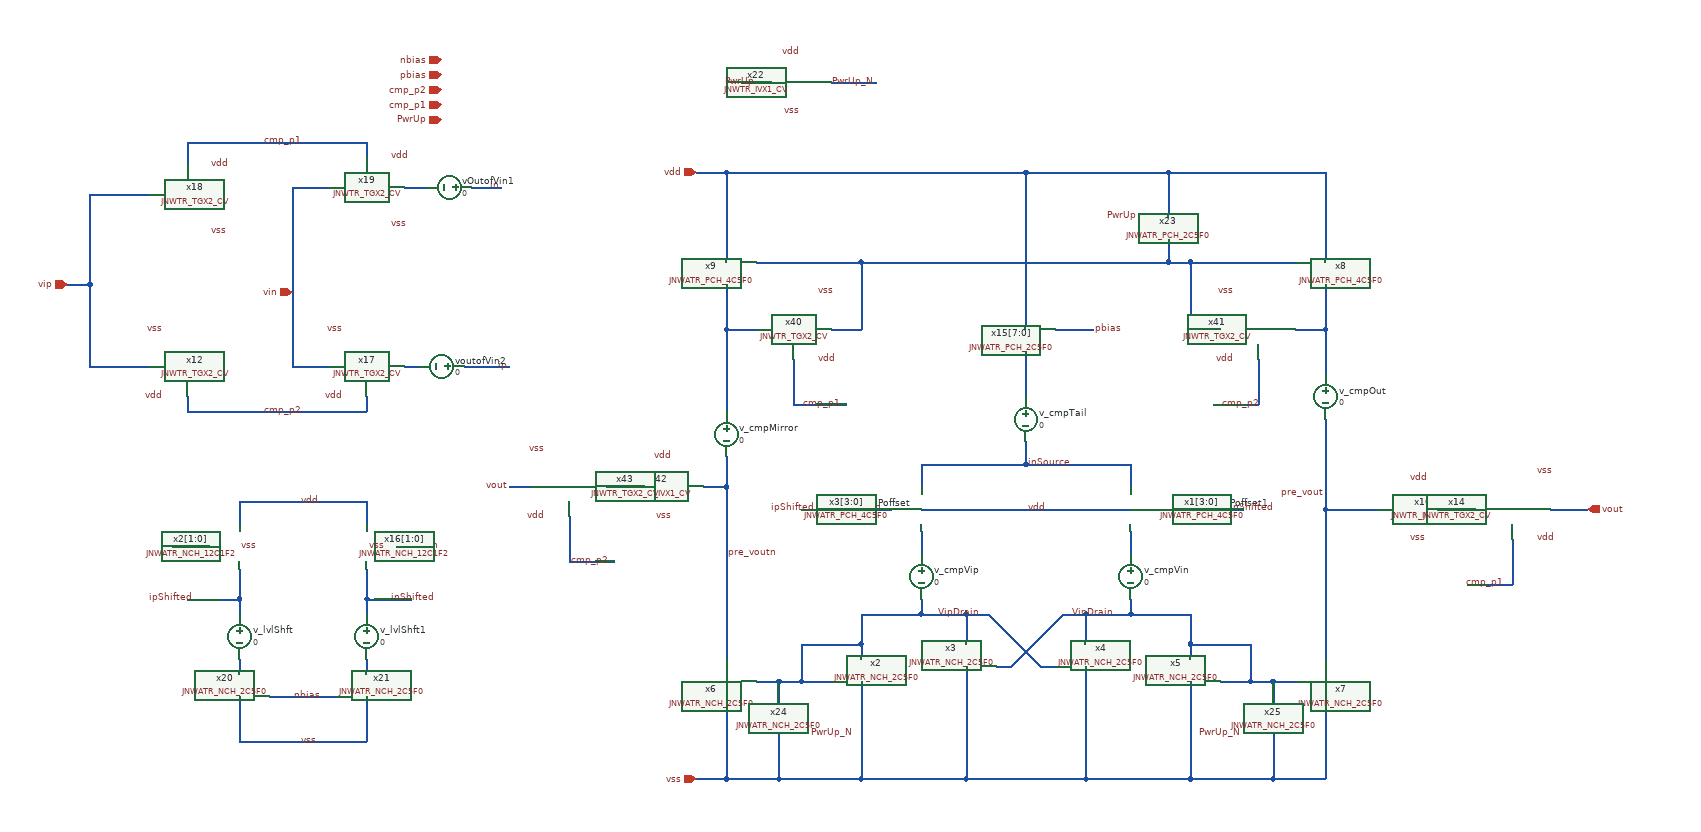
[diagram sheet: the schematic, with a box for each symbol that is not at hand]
v {xschem version=3.4.6 file_version=1.2}
G {}
K {}
V {}
S {}
E {}
N 1470 -450 1470 -410 {
lab=VipDrain}
N 1550 -450 1610 -450 {
lab=VipDrain}
N 1610 -450 1610 -410 {
lab=VipDrain}
N 1770 -450 1770 -410 {
lab=VinDrain}
N 1830 -450 1910 -450 {
lab=VinDrain}
N 1910 -410 1910 -390 {
lab=VinDrain}
N 1650 -380 1670 -380 {
lab=VinDrain}
N 1670 -380 1740 -450 {
lab=VinDrain}
N 1710 -380 1730 -380 {
lab=VipDrain}
N 1640 -450 1710 -380 {
lab=VipDrain}
N 1610 -450 1640 -450 {
lab=VipDrain}
N 1740 -450 1770 -450 {
lab=VinDrain}
N 1610 -380 1610 -230 {
lab=vss}
N 1770 -380 1770 -230 {
lab=vss}
N 2020 -230 2090 -230 {
lab=vss}
N 1470 -230 1610 -230 {
lab=vss}
N 1610 -230 1770 -230 {
lab=vss}
N 1770 -230 1910 -230 {
lab=vss}
N 1910 -360 1910 -230 {
lab=vss}
N 1470 -360 1470 -230 {
lab=vss}
N 1390 -360 1430 -360 {
lab=VipDrain}
N 1390 -410 1470 -410 {
lab=VipDrain}
N 1390 -410 1390 -360 {
lab=VipDrain}
N 1360 -360 1390 -360 {
lab=VipDrain}
N 1470 -410 1470 -390 {
lab=VipDrain}
N 1990 -410 1990 -360 {
lab=VinDrain}
N 1910 -410 1990 -410 {
lab=VinDrain}
N 1910 -450 1910 -410 {
lab=VinDrain}
N 1950 -360 1990 -360 {
lab=VinDrain}
N 1290 -360 1290 -230 {
lab=vss}
N 2090 -360 2090 -230 {
lab=vss}
N 2090 -590 2090 -390 {
lab=pre_vout}
N 2020 -360 2050 -360 {
lab=VinDrain}
N 1470 -920 1470 -830 {
lab=#net1}
N 1330 -920 1470 -920 {
lab=#net1}
N 1290 -1040 1290 -920 {
lab=vdd}
N 2090 -1040 2090 -920 {
lab=vdd}
N 1250 -1040 1290 -1040 {
lab=vdd}
N 1360 -230 1470 -230 {
lab=vss}
N 1250 -230 1290 -230 {
lab=vss}
N 2090 -590 2160 -590 {
lab=pre_vout}
N 1550 -650 1550 -620 {
lab=inSource}
N 1830 -650 1830 -620 {
lab=inSource}
N 1290 -830 1290 -720 {
lab=#net2}
N 2340 -550 2340 -490 {
lab=cmp_p1}
N 2280 -490 2340 -490 {
lab=cmp_p1}
N 2390 -590 2440 -590 {
lab=vout}
N 440 -890 440 -780 {
lab=vip}
N 440 -1010 520 -1010 {
lab=vip}
N 440 -780 520 -780 {
lab=vip}
N 710 -1020 710 -780 {
lab=vin}
N 710 -1020 760 -1020 {
lab=vin}
N 710 -780 760 -780 {
lab=vin}
N 570 -740 570 -720 {
lab=cmp_p2}
N 570 -720 810 -720 {
lab=cmp_p2}
N 810 -740 810 -720 {
lab=cmp_p2}
N 570 -1080 570 -1050 {
lab=cmp_p1}
N 570 -1080 810 -1080 {
lab=cmp_p1}
N 810 -1080 810 -1060 {
lab=cmp_p1}
N 1690 -1040 1690 -830 {lab=vdd}
N 1290 -1040 1690 -1040 {
lab=vdd}
N 1690 -680 1690 -650 {lab=inSource}
N 1390 -590 1420 -590 {lab=ipShifted}
N 1480 -590 1510 -590 {lab=ipm}
N 440 -1010 440 -890 {
lab=vip}
N 1870 -590 1890 -590 {lab=#net3}
N 1950 -590 1980 -590 {lab=inShifted}
N 1290 -620 1290 -390 {lab=pre_voutn}
N 2090 -710 2090 -590 {lab=pre_vout}
N 1830 -560 1830 -530 {lab=#net4}
N 1830 -470 1830 -450 {lab=VinDrain}
N 1770 -450 1830 -450 {
lab=VinDrain}
N 1550 -560 1550 -530 {lab=#net5}
N 1550 -470 1550 -450 {lab=VipDrain}
N 1470 -450 1550 -450 {
lab=VipDrain}
N 1730 -830 1780 -830 {lab=pbias}
N 1690 -800 1690 -740 {lab=#net6}
N 550 -540 600 -540 {lab=ip}
N 1550 -650 1690 -650 {
lab=inSource}
N 1690 -650 1830 -650 {
lab=inSource}
N 1550 -590 1830 -590 {lab=vdd}
N 640 -600 810 -600 {lab=vdd}
N 640 -600 640 -570 {lab=vdd}
N 810 -600 810 -570 {lab=vdd}
N 680 -340 770 -340 {lab=nbias}
N 850 -540 890 -540 {lab=in}
N 810 -340 810 -280 {lab=vss}
N 640 -280 810 -280 {lab=vss}
N 640 -340 640 -280 {lab=vss}
N 570 -470 640 -470 {lab=ipShifted}
N 810 -470 870 -470 {lab=inShifted}
N 810 -510 810 -470 {lab=inShifted}
N 640 -510 640 -470 {lab=ipShifted}
N 810 -470 810 -450 {lab=inShifted}
N 810 -390 810 -370 {lab=#net7}
N 640 -470 640 -450 {lab=ipShifted}
N 640 -390 640 -370 {lab=#net8}
N 410 -890 440 -890 {lab=vip}
N 1310 -1160 1350 -1160 {lab=PwrUp}
N 1430 -1160 1490 -1160 {lab=PwrUp_N}
N 1880 -950 1880 -920 {lab=#net1}
N 1910 -920 2050 -920 {lab=#net1}
N 1470 -920 1880 -920 {
lab=#net1}
N 1880 -1040 1880 -980 {lab=vdd}
N 1880 -1040 2090 -1040 {lab=vdd}
N 1690 -1040 1880 -1040 {
lab=vdd}
N 1360 -360 1360 -320 {lab=VipDrain}
N 1330 -360 1360 -360 {
lab=VipDrain}
N 1290 -230 1360 -230 {
lab=vss}
N 1360 -290 1360 -230 {lab=vss}
N 2020 -360 2020 -320 {lab=VinDrain}
N 2020 -290 2020 -230 {lab=vss}
N 1990 -360 2020 -360 {
lab=VinDrain}
N 1910 -230 2020 -230 {
lab=vss}
N 860 -780 880 -780 {lab=#net9}
N 940 -780 1000 -780 {lab=ip}
N 860 -1020 890 -1020 {lab=#net10}
N 950 -1020 990 -1020 {lab=in}
N 2240 -590 2290 -590 {lab=#net11}
N 1880 -920 1910 -920 {lab=#net1}
N 1910 -920 1910 -830 {lab=#net1}
N 1430 -830 1470 -830 {
lab=#net1}
N 1380 -790 1380 -730 {
lab=cmp_p1}
N 1380 -730 1450 -730 {
lab=cmp_p1}
N 2000 -790 2000 -730 {
lab=cmp_p2}
N 1940 -730 2000 -730 {
lab=cmp_p2}
N 1290 -830 1330 -830 {lab=#net2}
N 1290 -890 1290 -830 {
lab=#net2}
N 2050 -830 2090 -830 {lab=#net12}
N 2090 -830 2090 -770 {lab=#net12}
N 2090 -890 2090 -830 {lab=#net12}
N 1910 -830 1950 -830 {lab=#net1}
N 1130 -620 1180 -620 {
lab=#net13}
N 1080 -580 1080 -520 {
lab=cmp_p2}
N 1080 -520 1140 -520 {
lab=cmp_p2}
N 1000 -620 1030 -620 {
lab=vout}
N 1260 -620 1290 -620 {lab=pre_voutn}
N 1290 -660 1290 -620 {lab=pre_voutn}
C {devices/ipin.sym} 1250 -230 0 0 {name=p2 lab=vss
}
C {devices/ipin.sym} 1250 -1040 0 0 {name=p3 lab=vdd
}
C {devices/ipin.sym} 910 -1170 0 0 {name=p1 lab=pbias
}
C {devices/ipin.sym} 710 -880 0 0 {name=p5 lab=vin
}
C {devices/ipin.sym} 410 -890 0 0 {name=p6 lab=vip
}
C {JNW_ATR_SKY130A/JNWATR_NCH_2C5F0.sym} 1430 -360 0 0 {name=x2 }
C {JNW_ATR_SKY130A/JNWATR_NCH_2C5F0.sym} 1650 -380 0 1 {name=x3 }
C {JNW_ATR_SKY130A/JNWATR_NCH_2C5F0.sym} 1730 -380 0 0 {name=x4 }
C {JNW_ATR_SKY130A/JNWATR_NCH_2C5F0.sym} 1950 -360 0 1 {name=x5 }
C {JNW_ATR_SKY130A/JNWATR_NCH_2C5F0.sym} 1330 -360 0 1 {name=x6 }
C {JNW_ATR_SKY130A/JNWATR_NCH_2C5F0.sym} 2050 -360 0 0 {name=x7 }
C {JNW_ATR_SKY130A/JNWATR_PCH_4C5F0.sym} 2050 -920 0 0 {name=x8 }
C {JNW_ATR_SKY130A/JNWATR_PCH_4C5F0.sym} 1330 -920 0 1 {name=x9 }
C {devices/opin.sym} 2440 -590 0 0 {name=p7 lab=vout}
C {JNW_TR_SKY130A/JNWTR_IVX1_CV.sym} 2160 -590 0 0 {name=x10 }
C {devices/ipin.sym} 910 -1130 0 0 {name=p10 lab=cmp_p1
}
C {devices/lab_wire.sym} 2200 -550 0 1 {name=p19 sig_type=std_logic lab=vss}
C {JNW_TR_SKY130A/JNWTR_TGX2_CV.sym} 2280 -590 2 1 {name=x14 }
C {devices/lab_wire.sym} 2370 -550 0 1 {name=p20 sig_type=std_logic lab=vdd}
C {devices/lab_wire.sym} 2370 -640 0 1 {name=p21 sig_type=std_logic lab=vss}
C {devices/lab_wire.sym} 2330 -490 0 0 {name=p22 sig_type=std_logic lab=cmp_p1}
C {devices/lab_wire.sym} 620 -780 0 0 {name=p32 sig_type=std_logic lab=in}
C {devices/lab_wire.sym} 620 -1010 0 0 {name=p33 sig_type=std_logic lab=ip}
C {devices/lab_wire.sym} 570 -540 0 0 {name=p34 sig_type=std_logic lab=ip}
C {devices/lab_wire.sym} 890 -540 0 1 {name=p35 sig_type=std_logic lab=in}
C {devices/ipin.sym} 910 -1150 0 0 {name=p11 lab=cmp_p2
}
C {devices/lab_wire.sym} 1810 -450 0 0 {name=p12 sig_type=std_logic lab=VinDrain}
C {devices/lab_wire.sym} 1570 -450 0 1 {name=p13 sig_type=std_logic lab=VipDrain}
C {devices/lab_wire.sym} 1290 -530 0 1 {name=p37 sig_type=std_logic lab=pre_voutn}
C {devices/lab_wire.sym} 2090 -610 0 0 {name=p38 sig_type=std_logic lab=pre_vout}
C {JNW_TR_SKY130A/JNWTR_TGX2_CV.sym} 630 -780 2 0 {name=x12 }
C {devices/lab_wire.sym} 540 -740 0 0 {name=p29 sig_type=std_logic lab=vdd}
C {devices/lab_wire.sym} 540 -830 0 0 {name=p30 sig_type=std_logic lab=vss}
C {JNW_TR_SKY130A/JNWTR_TGX2_CV.sym} 870 -780 2 0 {name=x17 }
C {devices/lab_wire.sym} 780 -740 0 0 {name=p31 sig_type=std_logic lab=vdd}
C {devices/lab_wire.sym} 780 -830 0 0 {name=p36 sig_type=std_logic lab=vss}
C {JNW_TR_SKY130A/JNWTR_TGX2_CV.sym} 510 -1010 0 0 {name=x18 }
C {devices/lab_wire.sym} 600 -1050 2 0 {name=p39 sig_type=std_logic lab=vdd}
C {devices/lab_wire.sym} 600 -960 2 0 {name=p40 sig_type=std_logic lab=vss}
C {JNW_TR_SKY130A/JNWTR_TGX2_CV.sym} 750 -1020 0 0 {name=x19 }
C {devices/lab_wire.sym} 840 -1060 2 0 {name=p41 sig_type=std_logic lab=vdd}
C {devices/lab_wire.sym} 840 -970 2 0 {name=p42 sig_type=std_logic lab=vss}
C {devices/lab_wire.sym} 1000 -780 0 0 {name=p43 sig_type=std_logic lab=ip}
C {devices/lab_wire.sym} 990 -1020 0 0 {name=p44 sig_type=std_logic lab=in}
C {devices/lab_wire.sym} 670 -720 0 1 {name=p45 sig_type=std_logic lab=cmp_p2}
C {devices/lab_wire.sym} 670 -1080 0 1 {name=p46 sig_type=std_logic lab=cmp_p1}
C {JNW_ATR_SKY130A/JNWATR_PCH_2C5F0.sym} 1730 -830 0 1 {name=x15[7:0]}
C {devices/vsource.sym} 1690 -710 0 0 {name=v_cmpTail value=0 savecurrent=true}
C {devices/lab_wire.sym} 1690 -650 0 1 {name=p47 sig_type=std_logic lab=inSource}
C {devices/vsource.sym} 1450 -590 1 0 {name=vCMPoffset value=0 savecurrent=false}
C {devices/lab_wire.sym} 2200 -630 0 1 {name=p48 sig_type=std_logic lab=vdd}
C {devices/lab_wire.sym} 1500 -590 0 0 {name=p8 sig_type=std_logic lab=ipm}
C {devices/vsource.sym} 1920 -590 1 0 {name=vCMPoffset1 value=0 savecurrent=false}
C {devices/vsource.sym} 1290 -690 0 0 {name=v_cmpMirror value=0 savecurrent=true}
C {devices/vsource.sym} 2090 -740 0 0 {name=v_cmpOut value=0 savecurrent=true}
C {devices/vsource.sym} 1830 -500 0 0 {name=v_cmpVin value=0 savecurrent=true}
C {devices/vsource.sym} 1550 -500 0 0 {name=v_cmpVip value=0 savecurrent=true}
C {devices/lab_wire.sym} 1780 -830 0 1 {name=p23 sig_type=std_logic lab=pbias}
C {devices/ipin.sym} 910 -1190 0 0 {name=p9 lab=nbias
}
C {JNW_ATR_SKY130A/JNWATR_NCH_12C1F2.sym} 600 -540 0 0 {name=x2[1:0]}
C {JNW_ATR_SKY130A/JNWATR_NCH_12C1F2.sym} 850 -540 0 1 {name=x16[1:0]}
C {devices/lab_wire.sym} 810 -540 0 1 {name=p14 sig_type=std_logic lab=vss}
C {devices/lab_wire.sym} 640 -540 0 1 {name=p15 sig_type=std_logic lab=vss}
C {JNW_ATR_SKY130A/JNWATR_PCH_4C5F0.sym} 1510 -590 0 0 {name=x3[3:0]}
C {devices/lab_wire.sym} 1690 -590 0 1 {name=p4 sig_type=std_logic lab=vdd}
C {devices/lab_wire.sym} 720 -600 0 1 {name=p16 sig_type=std_logic lab=vdd}
C {JNW_ATR_SKY130A/JNWATR_NCH_2C5F0.sym} 680 -340 0 1 {name=x20 }
C {JNW_ATR_SKY130A/JNWATR_NCH_2C5F0.sym} 770 -340 0 0 {name=x21 }
C {devices/lab_wire.sym} 720 -280 0 1 {name=p17 sig_type=std_logic lab=vss}
C {devices/lab_wire.sym} 710 -340 0 1 {name=p24 sig_type=std_logic lab=nbias}
C {devices/lab_wire.sym} 580 -470 0 0 {name=p25 sig_type=std_logic lab=ipShifted}
C {devices/lab_wire.sym} 840 -470 0 1 {name=p26 sig_type=std_logic lab=inShifted}
C {devices/lab_wire.sym} 1960 -590 0 1 {name=p27 sig_type=std_logic lab=inShifted}
C {devices/lab_wire.sym} 1410 -590 0 0 {name=p28 sig_type=std_logic lab=ipShifted}
C {devices/vsource.sym} 640 -420 0 0 {name=v_lvlShft value=0 savecurrent=true}
C {devices/vsource.sym} 810 -420 0 0 {name=v_lvlShft1 value=0 savecurrent=true}
C {JNW_ATR_SKY130A/JNWATR_PCH_4C5F0.sym} 1870 -590 0 1 {name=x1[3:0]}
C {JNW_TR_SKY130A/JNWTR_IVX1_CV.sym} 1350 -1160 0 0 {name=x22 }
C {devices/lab_wire.sym} 1330 -1160 0 0 {name=p50 sig_type=std_logic lab=PwrUp}
C {devices/lab_wire.sym} 1490 -1160 0 0 {name=p55 sig_type=std_logic lab=PwrUp_N}
C {devices/lab_wire.sym} 1390 -1120 0 0 {name=p56 sig_type=std_logic lab=vss}
C {devices/lab_wire.sym} 1390 -1200 0 0 {name=p57 sig_type=std_logic lab=vdd}
C {JNW_ATR_SKY130A/JNWATR_PCH_2C5F0.sym} 1840 -980 0 0 {name=x23 }
C {devices/lab_wire.sym} 1840 -980 0 0 {name=p58 sig_type=std_logic lab=PwrUp}
C {JNW_ATR_SKY130A/JNWATR_NCH_2C5F0.sym} 1400 -290 0 1 {name=x24 }
C {devices/lab_wire.sym} 1400 -290 0 1 {name=p59 sig_type=std_logic lab=PwrUp_N}
C {JNW_ATR_SKY130A/JNWATR_NCH_2C5F0.sym} 1980 -290 0 0 {name=x25 }
C {devices/lab_wire.sym} 1980 -290 0 0 {name=p60 sig_type=std_logic lab=PwrUp_N}
C {devices/ipin.sym} 910 -1110 0 0 {name=p61 lab=PwrUp
}
C {devices/vsource.sym} 910 -780 1 0 {name=voutofVin2 value=0 savecurrent=false}
C {devices/vsource.sym} 920 -1020 1 0 {name=vOutofVin1 value=0 savecurrent=false}
C {JNW_TR_SKY130A/JNWTR_TGX2_CV.sym} 1320 -830 2 1 {name=x40 }
C {devices/lab_wire.sym} 1410 -790 0 1 {name=p65 sig_type=std_logic lab=vdd}
C {devices/lab_wire.sym} 1410 -880 0 1 {name=p66 sig_type=std_logic lab=vss}
C {devices/lab_wire.sym} 1390 -730 0 1 {name=p87 sig_type=std_logic lab=cmp_p1}
C {JNW_TR_SKY130A/JNWTR_TGX2_CV.sym} 2060 -830 2 0 {name=x41 }
C {devices/lab_wire.sym} 1970 -790 0 0 {name=p88 sig_type=std_logic lab=vdd}
C {devices/lab_wire.sym} 1970 -880 0 0 {name=p96 sig_type=std_logic lab=vss}
C {devices/lab_wire.sym} 1950 -730 0 1 {name=p97 sig_type=std_logic lab=cmp_p2}
C {JNW_TR_SKY130A/JNWTR_IVX1_CV.sym} 1260 -620 0 1 {name=x42 }
C {devices/lab_wire.sym} 1220 -660 0 0 {name=p98 sig_type=std_logic lab=vdd}
C {devices/lab_wire.sym} 1220 -580 0 0 {name=p99 sig_type=std_logic lab=vss}
C {JNW_TR_SKY130A/JNWTR_TGX2_CV.sym} 1140 -620 2 0 {name=x43 }
C {devices/lab_wire.sym} 1050 -580 0 0 {name=p100 sig_type=std_logic lab=vdd}
C {devices/lab_wire.sym} 1050 -670 0 0 {name=p101 sig_type=std_logic lab=vss}
C {devices/lab_wire.sym} 1080 -520 0 1 {name=p102 sig_type=std_logic lab=cmp_p2}
C {devices/lab_wire.sym} 1000 -620 0 0 {name=p103 sig_type=std_logic lab=vout}
